# Generated by innovus_enablement/scripts/gen_fakeram.py: abstract 512x64 SRAM.
# Geometry is an assumption (see script header), not PDK data.
VERSION 5.8 ;
BUSBITCHARS "[]" ;
DIVIDERCHAR "/" ;

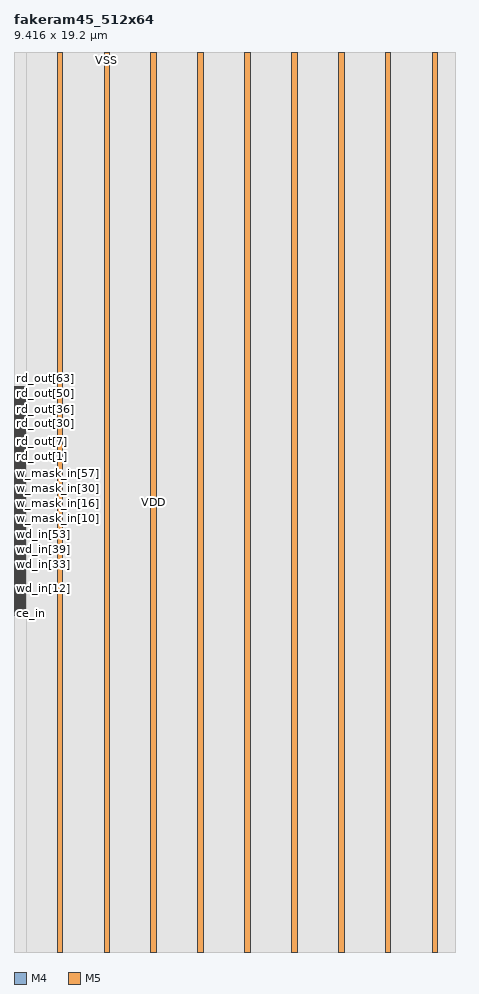
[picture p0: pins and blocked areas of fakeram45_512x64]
MACRO fakeram45_512x64
  CLASS BLOCK ;
  FOREIGN fakeram45_512x64 0 0 ;
  ORIGIN 0 0 ;
  SIZE 9.4160 BY 19.2000 ;
  SYMMETRY X Y R90 ;
  PIN clk
    DIRECTION INPUT ;
    USE CLOCK ;
    PORT
      LAYER M4 ;
        RECT 0 7.1820 0.2400 7.1940 ;
    END
  END clk
  PIN ce_in
    DIRECTION INPUT ;
    USE SIGNAL ;
    PORT
      LAYER M4 ;
        RECT 0 7.2060 0.2400 7.2180 ;
    END
  END ce_in
  PIN we_in
    DIRECTION INPUT ;
    USE SIGNAL ;
    PORT
      LAYER M4 ;
        RECT 0 7.2300 0.2400 7.2420 ;
    END
  END we_in
  PIN addr_in[0]
    DIRECTION INPUT ;
    USE SIGNAL ;
    PORT
      LAYER M4 ;
        RECT 0 7.2540 0.2400 7.2660 ;
    END
  END addr_in[0]
  PIN addr_in[1]
    DIRECTION INPUT ;
    USE SIGNAL ;
    PORT
      LAYER M4 ;
        RECT 0 7.2780 0.2400 7.2900 ;
    END
  END addr_in[1]
  PIN addr_in[2]
    DIRECTION INPUT ;
    USE SIGNAL ;
    PORT
      LAYER M4 ;
        RECT 0 7.3020 0.2400 7.3140 ;
    END
  END addr_in[2]
  PIN addr_in[3]
    DIRECTION INPUT ;
    USE SIGNAL ;
    PORT
      LAYER M4 ;
        RECT 0 7.3260 0.2400 7.3380 ;
    END
  END addr_in[3]
  PIN addr_in[4]
    DIRECTION INPUT ;
    USE SIGNAL ;
    PORT
      LAYER M4 ;
        RECT 0 7.3500 0.2400 7.3620 ;
    END
  END addr_in[4]
  PIN addr_in[5]
    DIRECTION INPUT ;
    USE SIGNAL ;
    PORT
      LAYER M4 ;
        RECT 0 7.3740 0.2400 7.3860 ;
    END
  END addr_in[5]
  PIN addr_in[6]
    DIRECTION INPUT ;
    USE SIGNAL ;
    PORT
      LAYER M4 ;
        RECT 0 7.3980 0.2400 7.4100 ;
    END
  END addr_in[6]
  PIN addr_in[7]
    DIRECTION INPUT ;
    USE SIGNAL ;
    PORT
      LAYER M4 ;
        RECT 0 7.4220 0.2400 7.4340 ;
    END
  END addr_in[7]
  PIN addr_in[8]
    DIRECTION INPUT ;
    USE SIGNAL ;
    PORT
      LAYER M4 ;
        RECT 0 7.4460 0.2400 7.4580 ;
    END
  END addr_in[8]
  PIN wd_in[0]
    DIRECTION INPUT ;
    USE SIGNAL ;
    PORT
      LAYER M4 ;
        RECT 0 7.4700 0.2400 7.4820 ;
    END
  END wd_in[0]
  PIN wd_in[1]
    DIRECTION INPUT ;
    USE SIGNAL ;
    PORT
      LAYER M4 ;
        RECT 0 7.4940 0.2400 7.5060 ;
    END
  END wd_in[1]
  PIN wd_in[2]
    DIRECTION INPUT ;
    USE SIGNAL ;
    PORT
      LAYER M4 ;
        RECT 0 7.5180 0.2400 7.5300 ;
    END
  END wd_in[2]
  PIN wd_in[3]
    DIRECTION INPUT ;
    USE SIGNAL ;
    PORT
      LAYER M4 ;
        RECT 0 7.5420 0.2400 7.5540 ;
    END
  END wd_in[3]
  PIN wd_in[4]
    DIRECTION INPUT ;
    USE SIGNAL ;
    PORT
      LAYER M4 ;
        RECT 0 7.5660 0.2400 7.5780 ;
    END
  END wd_in[4]
  PIN wd_in[5]
    DIRECTION INPUT ;
    USE SIGNAL ;
    PORT
      LAYER M4 ;
        RECT 0 7.5900 0.2400 7.6020 ;
    END
  END wd_in[5]
  PIN wd_in[6]
    DIRECTION INPUT ;
    USE SIGNAL ;
    PORT
      LAYER M4 ;
        RECT 0 7.6140 0.2400 7.6260 ;
    END
  END wd_in[6]
  PIN wd_in[7]
    DIRECTION INPUT ;
    USE SIGNAL ;
    PORT
      LAYER M4 ;
        RECT 0 7.6380 0.2400 7.6500 ;
    END
  END wd_in[7]
  PIN wd_in[8]
    DIRECTION INPUT ;
    USE SIGNAL ;
    PORT
      LAYER M4 ;
        RECT 0 7.6620 0.2400 7.6740 ;
    END
  END wd_in[8]
  PIN wd_in[9]
    DIRECTION INPUT ;
    USE SIGNAL ;
    PORT
      LAYER M4 ;
        RECT 0 7.6860 0.2400 7.6980 ;
    END
  END wd_in[9]
  PIN wd_in[10]
    DIRECTION INPUT ;
    USE SIGNAL ;
    PORT
      LAYER M4 ;
        RECT 0 7.7100 0.2400 7.7220 ;
    END
  END wd_in[10]
  PIN wd_in[11]
    DIRECTION INPUT ;
    USE SIGNAL ;
    PORT
      LAYER M4 ;
        RECT 0 7.7340 0.2400 7.7460 ;
    END
  END wd_in[11]
  PIN wd_in[12]
    DIRECTION INPUT ;
    USE SIGNAL ;
    PORT
      LAYER M4 ;
        RECT 0 7.7580 0.2400 7.7700 ;
    END
  END wd_in[12]
  PIN wd_in[13]
    DIRECTION INPUT ;
    USE SIGNAL ;
    PORT
      LAYER M4 ;
        RECT 0 7.7820 0.2400 7.7940 ;
    END
  END wd_in[13]
  PIN wd_in[14]
    DIRECTION INPUT ;
    USE SIGNAL ;
    PORT
      LAYER M4 ;
        RECT 0 7.8060 0.2400 7.8180 ;
    END
  END wd_in[14]
  PIN wd_in[15]
    DIRECTION INPUT ;
    USE SIGNAL ;
    PORT
      LAYER M4 ;
        RECT 0 7.8300 0.2400 7.8420 ;
    END
  END wd_in[15]
  PIN wd_in[16]
    DIRECTION INPUT ;
    USE SIGNAL ;
    PORT
      LAYER M4 ;
        RECT 0 7.8540 0.2400 7.8660 ;
    END
  END wd_in[16]
  PIN wd_in[17]
    DIRECTION INPUT ;
    USE SIGNAL ;
    PORT
      LAYER M4 ;
        RECT 0 7.8780 0.2400 7.8900 ;
    END
  END wd_in[17]
  PIN wd_in[18]
    DIRECTION INPUT ;
    USE SIGNAL ;
    PORT
      LAYER M4 ;
        RECT 0 7.9020 0.2400 7.9140 ;
    END
  END wd_in[18]
  PIN wd_in[19]
    DIRECTION INPUT ;
    USE SIGNAL ;
    PORT
      LAYER M4 ;
        RECT 0 7.9260 0.2400 7.9380 ;
    END
  END wd_in[19]
  PIN wd_in[20]
    DIRECTION INPUT ;
    USE SIGNAL ;
    PORT
      LAYER M4 ;
        RECT 0 7.9500 0.2400 7.9620 ;
    END
  END wd_in[20]
  PIN wd_in[21]
    DIRECTION INPUT ;
    USE SIGNAL ;
    PORT
      LAYER M4 ;
        RECT 0 7.9740 0.2400 7.9860 ;
    END
  END wd_in[21]
  PIN wd_in[22]
    DIRECTION INPUT ;
    USE SIGNAL ;
    PORT
      LAYER M4 ;
        RECT 0 7.9980 0.2400 8.0100 ;
    END
  END wd_in[22]
  PIN wd_in[23]
    DIRECTION INPUT ;
    USE SIGNAL ;
    PORT
      LAYER M4 ;
        RECT 0 8.0220 0.2400 8.0340 ;
    END
  END wd_in[23]
  PIN wd_in[24]
    DIRECTION INPUT ;
    USE SIGNAL ;
    PORT
      LAYER M4 ;
        RECT 0 8.0460 0.2400 8.0580 ;
    END
  END wd_in[24]
  PIN wd_in[25]
    DIRECTION INPUT ;
    USE SIGNAL ;
    PORT
      LAYER M4 ;
        RECT 0 8.0700 0.2400 8.0820 ;
    END
  END wd_in[25]
  PIN wd_in[26]
    DIRECTION INPUT ;
    USE SIGNAL ;
    PORT
      LAYER M4 ;
        RECT 0 8.0940 0.2400 8.1060 ;
    END
  END wd_in[26]
  PIN wd_in[27]
    DIRECTION INPUT ;
    USE SIGNAL ;
    PORT
      LAYER M4 ;
        RECT 0 8.1180 0.2400 8.1300 ;
    END
  END wd_in[27]
  PIN wd_in[28]
    DIRECTION INPUT ;
    USE SIGNAL ;
    PORT
      LAYER M4 ;
        RECT 0 8.1420 0.2400 8.1540 ;
    END
  END wd_in[28]
  PIN wd_in[29]
    DIRECTION INPUT ;
    USE SIGNAL ;
    PORT
      LAYER M4 ;
        RECT 0 8.1660 0.2400 8.1780 ;
    END
  END wd_in[29]
  PIN wd_in[30]
    DIRECTION INPUT ;
    USE SIGNAL ;
    PORT
      LAYER M4 ;
        RECT 0 8.1900 0.2400 8.2020 ;
    END
  END wd_in[30]
  PIN wd_in[31]
    DIRECTION INPUT ;
    USE SIGNAL ;
    PORT
      LAYER M4 ;
        RECT 0 8.2140 0.2400 8.2260 ;
    END
  END wd_in[31]
  PIN wd_in[32]
    DIRECTION INPUT ;
    USE SIGNAL ;
    PORT
      LAYER M4 ;
        RECT 0 8.2380 0.2400 8.2500 ;
    END
  END wd_in[32]
  PIN wd_in[33]
    DIRECTION INPUT ;
    USE SIGNAL ;
    PORT
      LAYER M4 ;
        RECT 0 8.2620 0.2400 8.2740 ;
    END
  END wd_in[33]
  PIN wd_in[34]
    DIRECTION INPUT ;
    USE SIGNAL ;
    PORT
      LAYER M4 ;
        RECT 0 8.2860 0.2400 8.2980 ;
    END
  END wd_in[34]
  PIN wd_in[35]
    DIRECTION INPUT ;
    USE SIGNAL ;
    PORT
      LAYER M4 ;
        RECT 0 8.3100 0.2400 8.3220 ;
    END
  END wd_in[35]
  PIN wd_in[36]
    DIRECTION INPUT ;
    USE SIGNAL ;
    PORT
      LAYER M4 ;
        RECT 0 8.3340 0.2400 8.3460 ;
    END
  END wd_in[36]
  PIN wd_in[37]
    DIRECTION INPUT ;
    USE SIGNAL ;
    PORT
      LAYER M4 ;
        RECT 0 8.3580 0.2400 8.3700 ;
    END
  END wd_in[37]
  PIN wd_in[38]
    DIRECTION INPUT ;
    USE SIGNAL ;
    PORT
      LAYER M4 ;
        RECT 0 8.3820 0.2400 8.3940 ;
    END
  END wd_in[38]
  PIN wd_in[39]
    DIRECTION INPUT ;
    USE SIGNAL ;
    PORT
      LAYER M4 ;
        RECT 0 8.4060 0.2400 8.4180 ;
    END
  END wd_in[39]
  PIN wd_in[40]
    DIRECTION INPUT ;
    USE SIGNAL ;
    PORT
      LAYER M4 ;
        RECT 0 8.4300 0.2400 8.4420 ;
    END
  END wd_in[40]
  PIN wd_in[41]
    DIRECTION INPUT ;
    USE SIGNAL ;
    PORT
      LAYER M4 ;
        RECT 0 8.4540 0.2400 8.4660 ;
    END
  END wd_in[41]
  PIN wd_in[42]
    DIRECTION INPUT ;
    USE SIGNAL ;
    PORT
      LAYER M4 ;
        RECT 0 8.4780 0.2400 8.4900 ;
    END
  END wd_in[42]
  PIN wd_in[43]
    DIRECTION INPUT ;
    USE SIGNAL ;
    PORT
      LAYER M4 ;
        RECT 0 8.5020 0.2400 8.5140 ;
    END
  END wd_in[43]
  PIN wd_in[44]
    DIRECTION INPUT ;
    USE SIGNAL ;
    PORT
      LAYER M4 ;
        RECT 0 8.5260 0.2400 8.5380 ;
    END
  END wd_in[44]
  PIN wd_in[45]
    DIRECTION INPUT ;
    USE SIGNAL ;
    PORT
      LAYER M4 ;
        RECT 0 8.5500 0.2400 8.5620 ;
    END
  END wd_in[45]
  PIN wd_in[46]
    DIRECTION INPUT ;
    USE SIGNAL ;
    PORT
      LAYER M4 ;
        RECT 0 8.5740 0.2400 8.5860 ;
    END
  END wd_in[46]
  PIN wd_in[47]
    DIRECTION INPUT ;
    USE SIGNAL ;
    PORT
      LAYER M4 ;
        RECT 0 8.5980 0.2400 8.6100 ;
    END
  END wd_in[47]
  PIN wd_in[48]
    DIRECTION INPUT ;
    USE SIGNAL ;
    PORT
      LAYER M4 ;
        RECT 0 8.6220 0.2400 8.6340 ;
    END
  END wd_in[48]
  PIN wd_in[49]
    DIRECTION INPUT ;
    USE SIGNAL ;
    PORT
      LAYER M4 ;
        RECT 0 8.6460 0.2400 8.6580 ;
    END
  END wd_in[49]
  PIN wd_in[50]
    DIRECTION INPUT ;
    USE SIGNAL ;
    PORT
      LAYER M4 ;
        RECT 0 8.6700 0.2400 8.6820 ;
    END
  END wd_in[50]
  PIN wd_in[51]
    DIRECTION INPUT ;
    USE SIGNAL ;
    PORT
      LAYER M4 ;
        RECT 0 8.6940 0.2400 8.7060 ;
    END
  END wd_in[51]
  PIN wd_in[52]
    DIRECTION INPUT ;
    USE SIGNAL ;
    PORT
      LAYER M4 ;
        RECT 0 8.7180 0.2400 8.7300 ;
    END
  END wd_in[52]
  PIN wd_in[53]
    DIRECTION INPUT ;
    USE SIGNAL ;
    PORT
      LAYER M4 ;
        RECT 0 8.7420 0.2400 8.7540 ;
    END
  END wd_in[53]
  PIN wd_in[54]
    DIRECTION INPUT ;
    USE SIGNAL ;
    PORT
      LAYER M4 ;
        RECT 0 8.7660 0.2400 8.7780 ;
    END
  END wd_in[54]
  PIN wd_in[55]
    DIRECTION INPUT ;
    USE SIGNAL ;
    PORT
      LAYER M4 ;
        RECT 0 8.7900 0.2400 8.8020 ;
    END
  END wd_in[55]
  PIN wd_in[56]
    DIRECTION INPUT ;
    USE SIGNAL ;
    PORT
      LAYER M4 ;
        RECT 0 8.8140 0.2400 8.8260 ;
    END
  END wd_in[56]
  PIN wd_in[57]
    DIRECTION INPUT ;
    USE SIGNAL ;
    PORT
      LAYER M4 ;
        RECT 0 8.8380 0.2400 8.8500 ;
    END
  END wd_in[57]
  PIN wd_in[58]
    DIRECTION INPUT ;
    USE SIGNAL ;
    PORT
      LAYER M4 ;
        RECT 0 8.8620 0.2400 8.8740 ;
    END
  END wd_in[58]
  PIN wd_in[59]
    DIRECTION INPUT ;
    USE SIGNAL ;
    PORT
      LAYER M4 ;
        RECT 0 8.8860 0.2400 8.8980 ;
    END
  END wd_in[59]
  PIN wd_in[60]
    DIRECTION INPUT ;
    USE SIGNAL ;
    PORT
      LAYER M4 ;
        RECT 0 8.9100 0.2400 8.9220 ;
    END
  END wd_in[60]
  PIN wd_in[61]
    DIRECTION INPUT ;
    USE SIGNAL ;
    PORT
      LAYER M4 ;
        RECT 0 8.9340 0.2400 8.9460 ;
    END
  END wd_in[61]
  PIN wd_in[62]
    DIRECTION INPUT ;
    USE SIGNAL ;
    PORT
      LAYER M4 ;
        RECT 0 8.9580 0.2400 8.9700 ;
    END
  END wd_in[62]
  PIN wd_in[63]
    DIRECTION INPUT ;
    USE SIGNAL ;
    PORT
      LAYER M4 ;
        RECT 0 8.9820 0.2400 8.9940 ;
    END
  END wd_in[63]
  PIN w_mask_in[0]
    DIRECTION INPUT ;
    USE SIGNAL ;
    PORT
      LAYER M4 ;
        RECT 0 9.0060 0.2400 9.0180 ;
    END
  END w_mask_in[0]
  PIN w_mask_in[1]
    DIRECTION INPUT ;
    USE SIGNAL ;
    PORT
      LAYER M4 ;
        RECT 0 9.0300 0.2400 9.0420 ;
    END
  END w_mask_in[1]
  PIN w_mask_in[2]
    DIRECTION INPUT ;
    USE SIGNAL ;
    PORT
      LAYER M4 ;
        RECT 0 9.0540 0.2400 9.0660 ;
    END
  END w_mask_in[2]
  PIN w_mask_in[3]
    DIRECTION INPUT ;
    USE SIGNAL ;
    PORT
      LAYER M4 ;
        RECT 0 9.0780 0.2400 9.0900 ;
    END
  END w_mask_in[3]
  PIN w_mask_in[4]
    DIRECTION INPUT ;
    USE SIGNAL ;
    PORT
      LAYER M4 ;
        RECT 0 9.1020 0.2400 9.1140 ;
    END
  END w_mask_in[4]
  PIN w_mask_in[5]
    DIRECTION INPUT ;
    USE SIGNAL ;
    PORT
      LAYER M4 ;
        RECT 0 9.1260 0.2400 9.1380 ;
    END
  END w_mask_in[5]
  PIN w_mask_in[6]
    DIRECTION INPUT ;
    USE SIGNAL ;
    PORT
      LAYER M4 ;
        RECT 0 9.1500 0.2400 9.1620 ;
    END
  END w_mask_in[6]
  PIN w_mask_in[7]
    DIRECTION INPUT ;
    USE SIGNAL ;
    PORT
      LAYER M4 ;
        RECT 0 9.1740 0.2400 9.1860 ;
    END
  END w_mask_in[7]
  PIN w_mask_in[8]
    DIRECTION INPUT ;
    USE SIGNAL ;
    PORT
      LAYER M4 ;
        RECT 0 9.1980 0.2400 9.2100 ;
    END
  END w_mask_in[8]
  PIN w_mask_in[9]
    DIRECTION INPUT ;
    USE SIGNAL ;
    PORT
      LAYER M4 ;
        RECT 0 9.2220 0.2400 9.2340 ;
    END
  END w_mask_in[9]
  PIN w_mask_in[10]
    DIRECTION INPUT ;
    USE SIGNAL ;
    PORT
      LAYER M4 ;
        RECT 0 9.2460 0.2400 9.2580 ;
    END
  END w_mask_in[10]
  PIN w_mask_in[11]
    DIRECTION INPUT ;
    USE SIGNAL ;
    PORT
      LAYER M4 ;
        RECT 0 9.2700 0.2400 9.2820 ;
    END
  END w_mask_in[11]
  PIN w_mask_in[12]
    DIRECTION INPUT ;
    USE SIGNAL ;
    PORT
      LAYER M4 ;
        RECT 0 9.2940 0.2400 9.3060 ;
    END
  END w_mask_in[12]
  PIN w_mask_in[13]
    DIRECTION INPUT ;
    USE SIGNAL ;
    PORT
      LAYER M4 ;
        RECT 0 9.3180 0.2400 9.3300 ;
    END
  END w_mask_in[13]
  PIN w_mask_in[14]
    DIRECTION INPUT ;
    USE SIGNAL ;
    PORT
      LAYER M4 ;
        RECT 0 9.3420 0.2400 9.3540 ;
    END
  END w_mask_in[14]
  PIN w_mask_in[15]
    DIRECTION INPUT ;
    USE SIGNAL ;
    PORT
      LAYER M4 ;
        RECT 0 9.3660 0.2400 9.3780 ;
    END
  END w_mask_in[15]
  PIN w_mask_in[16]
    DIRECTION INPUT ;
    USE SIGNAL ;
    PORT
      LAYER M4 ;
        RECT 0 9.3900 0.2400 9.4020 ;
    END
  END w_mask_in[16]
  PIN w_mask_in[17]
    DIRECTION INPUT ;
    USE SIGNAL ;
    PORT
      LAYER M4 ;
        RECT 0 9.4140 0.2400 9.4260 ;
    END
  END w_mask_in[17]
  PIN w_mask_in[18]
    DIRECTION INPUT ;
    USE SIGNAL ;
    PORT
      LAYER M4 ;
        RECT 0 9.4380 0.2400 9.4500 ;
    END
  END w_mask_in[18]
  PIN w_mask_in[19]
    DIRECTION INPUT ;
    USE SIGNAL ;
    PORT
      LAYER M4 ;
        RECT 0 9.4620 0.2400 9.4740 ;
    END
  END w_mask_in[19]
  PIN w_mask_in[20]
    DIRECTION INPUT ;
    USE SIGNAL ;
    PORT
      LAYER M4 ;
        RECT 0 9.4860 0.2400 9.4980 ;
    END
  END w_mask_in[20]
  PIN w_mask_in[21]
    DIRECTION INPUT ;
    USE SIGNAL ;
    PORT
      LAYER M4 ;
        RECT 0 9.5100 0.2400 9.5220 ;
    END
  END w_mask_in[21]
  PIN w_mask_in[22]
    DIRECTION INPUT ;
    USE SIGNAL ;
    PORT
      LAYER M4 ;
        RECT 0 9.5340 0.2400 9.5460 ;
    END
  END w_mask_in[22]
  PIN w_mask_in[23]
    DIRECTION INPUT ;
    USE SIGNAL ;
    PORT
      LAYER M4 ;
        RECT 0 9.5580 0.2400 9.5700 ;
    END
  END w_mask_in[23]
  PIN w_mask_in[24]
    DIRECTION INPUT ;
    USE SIGNAL ;
    PORT
      LAYER M4 ;
        RECT 0 9.5820 0.2400 9.5940 ;
    END
  END w_mask_in[24]
  PIN w_mask_in[25]
    DIRECTION INPUT ;
    USE SIGNAL ;
    PORT
      LAYER M4 ;
        RECT 0 9.6060 0.2400 9.6180 ;
    END
  END w_mask_in[25]
  PIN w_mask_in[26]
    DIRECTION INPUT ;
    USE SIGNAL ;
    PORT
      LAYER M4 ;
        RECT 0 9.6300 0.2400 9.6420 ;
    END
  END w_mask_in[26]
  PIN w_mask_in[27]
    DIRECTION INPUT ;
    USE SIGNAL ;
    PORT
      LAYER M4 ;
        RECT 0 9.6540 0.2400 9.6660 ;
    END
  END w_mask_in[27]
  PIN w_mask_in[28]
    DIRECTION INPUT ;
    USE SIGNAL ;
    PORT
      LAYER M4 ;
        RECT 0 9.6780 0.2400 9.6900 ;
    END
  END w_mask_in[28]
  PIN w_mask_in[29]
    DIRECTION INPUT ;
    USE SIGNAL ;
    PORT
      LAYER M4 ;
        RECT 0 9.7020 0.2400 9.7140 ;
    END
  END w_mask_in[29]
  PIN w_mask_in[30]
    DIRECTION INPUT ;
    USE SIGNAL ;
    PORT
      LAYER M4 ;
        RECT 0 9.7260 0.2400 9.7380 ;
    END
  END w_mask_in[30]
  PIN w_mask_in[31]
    DIRECTION INPUT ;
    USE SIGNAL ;
    PORT
      LAYER M4 ;
        RECT 0 9.7500 0.2400 9.7620 ;
    END
  END w_mask_in[31]
  PIN w_mask_in[32]
    DIRECTION INPUT ;
    USE SIGNAL ;
    PORT
      LAYER M4 ;
        RECT 0 9.7740 0.2400 9.7860 ;
    END
  END w_mask_in[32]
  PIN w_mask_in[33]
    DIRECTION INPUT ;
    USE SIGNAL ;
    PORT
      LAYER M4 ;
        RECT 0 9.7980 0.2400 9.8100 ;
    END
  END w_mask_in[33]
  PIN w_mask_in[34]
    DIRECTION INPUT ;
    USE SIGNAL ;
    PORT
      LAYER M4 ;
        RECT 0 9.8220 0.2400 9.8340 ;
    END
  END w_mask_in[34]
  PIN w_mask_in[35]
    DIRECTION INPUT ;
    USE SIGNAL ;
    PORT
      LAYER M4 ;
        RECT 0 9.8460 0.2400 9.8580 ;
    END
  END w_mask_in[35]
  PIN w_mask_in[36]
    DIRECTION INPUT ;
    USE SIGNAL ;
    PORT
      LAYER M4 ;
        RECT 0 9.8700 0.2400 9.8820 ;
    END
  END w_mask_in[36]
  PIN w_mask_in[37]
    DIRECTION INPUT ;
    USE SIGNAL ;
    PORT
      LAYER M4 ;
        RECT 0 9.8940 0.2400 9.9060 ;
    END
  END w_mask_in[37]
  PIN w_mask_in[38]
    DIRECTION INPUT ;
    USE SIGNAL ;
    PORT
      LAYER M4 ;
        RECT 0 9.9180 0.2400 9.9300 ;
    END
  END w_mask_in[38]
  PIN w_mask_in[39]
    DIRECTION INPUT ;
    USE SIGNAL ;
    PORT
      LAYER M4 ;
        RECT 0 9.9420 0.2400 9.9540 ;
    END
  END w_mask_in[39]
  PIN w_mask_in[40]
    DIRECTION INPUT ;
    USE SIGNAL ;
    PORT
      LAYER M4 ;
        RECT 0 9.9660 0.2400 9.9780 ;
    END
  END w_mask_in[40]
  PIN w_mask_in[41]
    DIRECTION INPUT ;
    USE SIGNAL ;
    PORT
      LAYER M4 ;
        RECT 0 9.9900 0.2400 10.0020 ;
    END
  END w_mask_in[41]
  PIN w_mask_in[42]
    DIRECTION INPUT ;
    USE SIGNAL ;
    PORT
      LAYER M4 ;
        RECT 0 10.0140 0.2400 10.0260 ;
    END
  END w_mask_in[42]
  PIN w_mask_in[43]
    DIRECTION INPUT ;
    USE SIGNAL ;
    PORT
      LAYER M4 ;
        RECT 0 10.0380 0.2400 10.0500 ;
    END
  END w_mask_in[43]
  PIN w_mask_in[44]
    DIRECTION INPUT ;
    USE SIGNAL ;
    PORT
      LAYER M4 ;
        RECT 0 10.0620 0.2400 10.0740 ;
    END
  END w_mask_in[44]
  PIN w_mask_in[45]
    DIRECTION INPUT ;
    USE SIGNAL ;
    PORT
      LAYER M4 ;
        RECT 0 10.0860 0.2400 10.0980 ;
    END
  END w_mask_in[45]
  PIN w_mask_in[46]
    DIRECTION INPUT ;
    USE SIGNAL ;
    PORT
      LAYER M4 ;
        RECT 0 10.1100 0.2400 10.1220 ;
    END
  END w_mask_in[46]
  PIN w_mask_in[47]
    DIRECTION INPUT ;
    USE SIGNAL ;
    PORT
      LAYER M4 ;
        RECT 0 10.1340 0.2400 10.1460 ;
    END
  END w_mask_in[47]
  PIN w_mask_in[48]
    DIRECTION INPUT ;
    USE SIGNAL ;
    PORT
      LAYER M4 ;
        RECT 0 10.1580 0.2400 10.1700 ;
    END
  END w_mask_in[48]
  PIN w_mask_in[49]
    DIRECTION INPUT ;
    USE SIGNAL ;
    PORT
      LAYER M4 ;
        RECT 0 10.1820 0.2400 10.1940 ;
    END
  END w_mask_in[49]
  PIN w_mask_in[50]
    DIRECTION INPUT ;
    USE SIGNAL ;
    PORT
      LAYER M4 ;
        RECT 0 10.2060 0.2400 10.2180 ;
    END
  END w_mask_in[50]
  PIN w_mask_in[51]
    DIRECTION INPUT ;
    USE SIGNAL ;
    PORT
      LAYER M4 ;
        RECT 0 10.2300 0.2400 10.2420 ;
    END
  END w_mask_in[51]
  PIN w_mask_in[52]
    DIRECTION INPUT ;
    USE SIGNAL ;
    PORT
      LAYER M4 ;
        RECT 0 10.2540 0.2400 10.2660 ;
    END
  END w_mask_in[52]
  PIN w_mask_in[53]
    DIRECTION INPUT ;
    USE SIGNAL ;
    PORT
      LAYER M4 ;
        RECT 0 10.2780 0.2400 10.2900 ;
    END
  END w_mask_in[53]
  PIN w_mask_in[54]
    DIRECTION INPUT ;
    USE SIGNAL ;
    PORT
      LAYER M4 ;
        RECT 0 10.3020 0.2400 10.3140 ;
    END
  END w_mask_in[54]
  PIN w_mask_in[55]
    DIRECTION INPUT ;
    USE SIGNAL ;
    PORT
      LAYER M4 ;
        RECT 0 10.3260 0.2400 10.3380 ;
    END
  END w_mask_in[55]
  PIN w_mask_in[56]
    DIRECTION INPUT ;
    USE SIGNAL ;
    PORT
      LAYER M4 ;
        RECT 0 10.3500 0.2400 10.3620 ;
    END
  END w_mask_in[56]
  PIN w_mask_in[57]
    DIRECTION INPUT ;
    USE SIGNAL ;
    PORT
      LAYER M4 ;
        RECT 0 10.3740 0.2400 10.3860 ;
    END
  END w_mask_in[57]
  PIN w_mask_in[58]
    DIRECTION INPUT ;
    USE SIGNAL ;
    PORT
      LAYER M4 ;
        RECT 0 10.3980 0.2400 10.4100 ;
    END
  END w_mask_in[58]
  PIN w_mask_in[59]
    DIRECTION INPUT ;
    USE SIGNAL ;
    PORT
      LAYER M4 ;
        RECT 0 10.4220 0.2400 10.4340 ;
    END
  END w_mask_in[59]
  PIN w_mask_in[60]
    DIRECTION INPUT ;
    USE SIGNAL ;
    PORT
      LAYER M4 ;
        RECT 0 10.4460 0.2400 10.4580 ;
    END
  END w_mask_in[60]
  PIN w_mask_in[61]
    DIRECTION INPUT ;
    USE SIGNAL ;
    PORT
      LAYER M4 ;
        RECT 0 10.4700 0.2400 10.4820 ;
    END
  END w_mask_in[61]
  PIN w_mask_in[62]
    DIRECTION INPUT ;
    USE SIGNAL ;
    PORT
      LAYER M4 ;
        RECT 0 10.4940 0.2400 10.5060 ;
    END
  END w_mask_in[62]
  PIN w_mask_in[63]
    DIRECTION INPUT ;
    USE SIGNAL ;
    PORT
      LAYER M4 ;
        RECT 0 10.5180 0.2400 10.5300 ;
    END
  END w_mask_in[63]
  PIN rd_out[0]
    DIRECTION OUTPUT ;
    USE SIGNAL ;
    PORT
      LAYER M4 ;
        RECT 0 10.5420 0.2400 10.5540 ;
    END
  END rd_out[0]
  PIN rd_out[1]
    DIRECTION OUTPUT ;
    USE SIGNAL ;
    PORT
      LAYER M4 ;
        RECT 0 10.5660 0.2400 10.5780 ;
    END
  END rd_out[1]
  PIN rd_out[2]
    DIRECTION OUTPUT ;
    USE SIGNAL ;
    PORT
      LAYER M4 ;
        RECT 0 10.5900 0.2400 10.6020 ;
    END
  END rd_out[2]
  PIN rd_out[3]
    DIRECTION OUTPUT ;
    USE SIGNAL ;
    PORT
      LAYER M4 ;
        RECT 0 10.6140 0.2400 10.6260 ;
    END
  END rd_out[3]
  PIN rd_out[4]
    DIRECTION OUTPUT ;
    USE SIGNAL ;
    PORT
      LAYER M4 ;
        RECT 0 10.6380 0.2400 10.6500 ;
    END
  END rd_out[4]
  PIN rd_out[5]
    DIRECTION OUTPUT ;
    USE SIGNAL ;
    PORT
      LAYER M4 ;
        RECT 0 10.6620 0.2400 10.6740 ;
    END
  END rd_out[5]
  PIN rd_out[6]
    DIRECTION OUTPUT ;
    USE SIGNAL ;
    PORT
      LAYER M4 ;
        RECT 0 10.6860 0.2400 10.6980 ;
    END
  END rd_out[6]
  PIN rd_out[7]
    DIRECTION OUTPUT ;
    USE SIGNAL ;
    PORT
      LAYER M4 ;
        RECT 0 10.7100 0.2400 10.7220 ;
    END
  END rd_out[7]
  PIN rd_out[8]
    DIRECTION OUTPUT ;
    USE SIGNAL ;
    PORT
      LAYER M4 ;
        RECT 0 10.7340 0.2400 10.7460 ;
    END
  END rd_out[8]
  PIN rd_out[9]
    DIRECTION OUTPUT ;
    USE SIGNAL ;
    PORT
      LAYER M4 ;
        RECT 0 10.7580 0.2400 10.7700 ;
    END
  END rd_out[9]
  PIN rd_out[10]
    DIRECTION OUTPUT ;
    USE SIGNAL ;
    PORT
      LAYER M4 ;
        RECT 0 10.7820 0.2400 10.7940 ;
    END
  END rd_out[10]
  PIN rd_out[11]
    DIRECTION OUTPUT ;
    USE SIGNAL ;
    PORT
      LAYER M4 ;
        RECT 0 10.8060 0.2400 10.8180 ;
    END
  END rd_out[11]
  PIN rd_out[12]
    DIRECTION OUTPUT ;
    USE SIGNAL ;
    PORT
      LAYER M4 ;
        RECT 0 10.8300 0.2400 10.8420 ;
    END
  END rd_out[12]
  PIN rd_out[13]
    DIRECTION OUTPUT ;
    USE SIGNAL ;
    PORT
      LAYER M4 ;
        RECT 0 10.8540 0.2400 10.8660 ;
    END
  END rd_out[13]
  PIN rd_out[14]
    DIRECTION OUTPUT ;
    USE SIGNAL ;
    PORT
      LAYER M4 ;
        RECT 0 10.8780 0.2400 10.8900 ;
    END
  END rd_out[14]
  PIN rd_out[15]
    DIRECTION OUTPUT ;
    USE SIGNAL ;
    PORT
      LAYER M4 ;
        RECT 0 10.9020 0.2400 10.9140 ;
    END
  END rd_out[15]
  PIN rd_out[16]
    DIRECTION OUTPUT ;
    USE SIGNAL ;
    PORT
      LAYER M4 ;
        RECT 0 10.9260 0.2400 10.9380 ;
    END
  END rd_out[16]
  PIN rd_out[17]
    DIRECTION OUTPUT ;
    USE SIGNAL ;
    PORT
      LAYER M4 ;
        RECT 0 10.9500 0.2400 10.9620 ;
    END
  END rd_out[17]
  PIN rd_out[18]
    DIRECTION OUTPUT ;
    USE SIGNAL ;
    PORT
      LAYER M4 ;
        RECT 0 10.9740 0.2400 10.9860 ;
    END
  END rd_out[18]
  PIN rd_out[19]
    DIRECTION OUTPUT ;
    USE SIGNAL ;
    PORT
      LAYER M4 ;
        RECT 0 10.9980 0.2400 11.0100 ;
    END
  END rd_out[19]
  PIN rd_out[20]
    DIRECTION OUTPUT ;
    USE SIGNAL ;
    PORT
      LAYER M4 ;
        RECT 0 11.0220 0.2400 11.0340 ;
    END
  END rd_out[20]
  PIN rd_out[21]
    DIRECTION OUTPUT ;
    USE SIGNAL ;
    PORT
      LAYER M4 ;
        RECT 0 11.0460 0.2400 11.0580 ;
    END
  END rd_out[21]
  PIN rd_out[22]
    DIRECTION OUTPUT ;
    USE SIGNAL ;
    PORT
      LAYER M4 ;
        RECT 0 11.0700 0.2400 11.0820 ;
    END
  END rd_out[22]
  PIN rd_out[23]
    DIRECTION OUTPUT ;
    USE SIGNAL ;
    PORT
      LAYER M4 ;
        RECT 0 11.0940 0.2400 11.1060 ;
    END
  END rd_out[23]
  PIN rd_out[24]
    DIRECTION OUTPUT ;
    USE SIGNAL ;
    PORT
      LAYER M4 ;
        RECT 0 11.1180 0.2400 11.1300 ;
    END
  END rd_out[24]
  PIN rd_out[25]
    DIRECTION OUTPUT ;
    USE SIGNAL ;
    PORT
      LAYER M4 ;
        RECT 0 11.1420 0.2400 11.1540 ;
    END
  END rd_out[25]
  PIN rd_out[26]
    DIRECTION OUTPUT ;
    USE SIGNAL ;
    PORT
      LAYER M4 ;
        RECT 0 11.1660 0.2400 11.1780 ;
    END
  END rd_out[26]
  PIN rd_out[27]
    DIRECTION OUTPUT ;
    USE SIGNAL ;
    PORT
      LAYER M4 ;
        RECT 0 11.1900 0.2400 11.2020 ;
    END
  END rd_out[27]
  PIN rd_out[28]
    DIRECTION OUTPUT ;
    USE SIGNAL ;
    PORT
      LAYER M4 ;
        RECT 0 11.2140 0.2400 11.2260 ;
    END
  END rd_out[28]
  PIN rd_out[29]
    DIRECTION OUTPUT ;
    USE SIGNAL ;
    PORT
      LAYER M4 ;
        RECT 0 11.2380 0.2400 11.2500 ;
    END
  END rd_out[29]
  PIN rd_out[30]
    DIRECTION OUTPUT ;
    USE SIGNAL ;
    PORT
      LAYER M4 ;
        RECT 0 11.2620 0.2400 11.2740 ;
    END
  END rd_out[30]
  PIN rd_out[31]
    DIRECTION OUTPUT ;
    USE SIGNAL ;
    PORT
      LAYER M4 ;
        RECT 0 11.2860 0.2400 11.2980 ;
    END
  END rd_out[31]
  PIN rd_out[32]
    DIRECTION OUTPUT ;
    USE SIGNAL ;
    PORT
      LAYER M4 ;
        RECT 0 11.3100 0.2400 11.3220 ;
    END
  END rd_out[32]
  PIN rd_out[33]
    DIRECTION OUTPUT ;
    USE SIGNAL ;
    PORT
      LAYER M4 ;
        RECT 0 11.3340 0.2400 11.3460 ;
    END
  END rd_out[33]
  PIN rd_out[34]
    DIRECTION OUTPUT ;
    USE SIGNAL ;
    PORT
      LAYER M4 ;
        RECT 0 11.3580 0.2400 11.3700 ;
    END
  END rd_out[34]
  PIN rd_out[35]
    DIRECTION OUTPUT ;
    USE SIGNAL ;
    PORT
      LAYER M4 ;
        RECT 0 11.3820 0.2400 11.3940 ;
    END
  END rd_out[35]
  PIN rd_out[36]
    DIRECTION OUTPUT ;
    USE SIGNAL ;
    PORT
      LAYER M4 ;
        RECT 0 11.4060 0.2400 11.4180 ;
    END
  END rd_out[36]
  PIN rd_out[37]
    DIRECTION OUTPUT ;
    USE SIGNAL ;
    PORT
      LAYER M4 ;
        RECT 0 11.4300 0.2400 11.4420 ;
    END
  END rd_out[37]
  PIN rd_out[38]
    DIRECTION OUTPUT ;
    USE SIGNAL ;
    PORT
      LAYER M4 ;
        RECT 0 11.4540 0.2400 11.4660 ;
    END
  END rd_out[38]
  PIN rd_out[39]
    DIRECTION OUTPUT ;
    USE SIGNAL ;
    PORT
      LAYER M4 ;
        RECT 0 11.4780 0.2400 11.4900 ;
    END
  END rd_out[39]
  PIN rd_out[40]
    DIRECTION OUTPUT ;
    USE SIGNAL ;
    PORT
      LAYER M4 ;
        RECT 0 11.5020 0.2400 11.5140 ;
    END
  END rd_out[40]
  PIN rd_out[41]
    DIRECTION OUTPUT ;
    USE SIGNAL ;
    PORT
      LAYER M4 ;
        RECT 0 11.5260 0.2400 11.5380 ;
    END
  END rd_out[41]
  PIN rd_out[42]
    DIRECTION OUTPUT ;
    USE SIGNAL ;
    PORT
      LAYER M4 ;
        RECT 0 11.5500 0.2400 11.5620 ;
    END
  END rd_out[42]
  PIN rd_out[43]
    DIRECTION OUTPUT ;
    USE SIGNAL ;
    PORT
      LAYER M4 ;
        RECT 0 11.5740 0.2400 11.5860 ;
    END
  END rd_out[43]
  PIN rd_out[44]
    DIRECTION OUTPUT ;
    USE SIGNAL ;
    PORT
      LAYER M4 ;
        RECT 0 11.5980 0.2400 11.6100 ;
    END
  END rd_out[44]
  PIN rd_out[45]
    DIRECTION OUTPUT ;
    USE SIGNAL ;
    PORT
      LAYER M4 ;
        RECT 0 11.6220 0.2400 11.6340 ;
    END
  END rd_out[45]
  PIN rd_out[46]
    DIRECTION OUTPUT ;
    USE SIGNAL ;
    PORT
      LAYER M4 ;
        RECT 0 11.6460 0.2400 11.6580 ;
    END
  END rd_out[46]
  PIN rd_out[47]
    DIRECTION OUTPUT ;
    USE SIGNAL ;
    PORT
      LAYER M4 ;
        RECT 0 11.6700 0.2400 11.6820 ;
    END
  END rd_out[47]
  PIN rd_out[48]
    DIRECTION OUTPUT ;
    USE SIGNAL ;
    PORT
      LAYER M4 ;
        RECT 0 11.6940 0.2400 11.7060 ;
    END
  END rd_out[48]
  PIN rd_out[49]
    DIRECTION OUTPUT ;
    USE SIGNAL ;
    PORT
      LAYER M4 ;
        RECT 0 11.7180 0.2400 11.7300 ;
    END
  END rd_out[49]
  PIN rd_out[50]
    DIRECTION OUTPUT ;
    USE SIGNAL ;
    PORT
      LAYER M4 ;
        RECT 0 11.7420 0.2400 11.7540 ;
    END
  END rd_out[50]
  PIN rd_out[51]
    DIRECTION OUTPUT ;
    USE SIGNAL ;
    PORT
      LAYER M4 ;
        RECT 0 11.7660 0.2400 11.7780 ;
    END
  END rd_out[51]
  PIN rd_out[52]
    DIRECTION OUTPUT ;
    USE SIGNAL ;
    PORT
      LAYER M4 ;
        RECT 0 11.7900 0.2400 11.8020 ;
    END
  END rd_out[52]
  PIN rd_out[53]
    DIRECTION OUTPUT ;
    USE SIGNAL ;
    PORT
      LAYER M4 ;
        RECT 0 11.8140 0.2400 11.8260 ;
    END
  END rd_out[53]
  PIN rd_out[54]
    DIRECTION OUTPUT ;
    USE SIGNAL ;
    PORT
      LAYER M4 ;
        RECT 0 11.8380 0.2400 11.8500 ;
    END
  END rd_out[54]
  PIN rd_out[55]
    DIRECTION OUTPUT ;
    USE SIGNAL ;
    PORT
      LAYER M4 ;
        RECT 0 11.8620 0.2400 11.8740 ;
    END
  END rd_out[55]
  PIN rd_out[56]
    DIRECTION OUTPUT ;
    USE SIGNAL ;
    PORT
      LAYER M4 ;
        RECT 0 11.8860 0.2400 11.8980 ;
    END
  END rd_out[56]
  PIN rd_out[57]
    DIRECTION OUTPUT ;
    USE SIGNAL ;
    PORT
      LAYER M4 ;
        RECT 0 11.9100 0.2400 11.9220 ;
    END
  END rd_out[57]
  PIN rd_out[58]
    DIRECTION OUTPUT ;
    USE SIGNAL ;
    PORT
      LAYER M4 ;
        RECT 0 11.9340 0.2400 11.9460 ;
    END
  END rd_out[58]
  PIN rd_out[59]
    DIRECTION OUTPUT ;
    USE SIGNAL ;
    PORT
      LAYER M4 ;
        RECT 0 11.9580 0.2400 11.9700 ;
    END
  END rd_out[59]
  PIN rd_out[60]
    DIRECTION OUTPUT ;
    USE SIGNAL ;
    PORT
      LAYER M4 ;
        RECT 0 11.9820 0.2400 11.9940 ;
    END
  END rd_out[60]
  PIN rd_out[61]
    DIRECTION OUTPUT ;
    USE SIGNAL ;
    PORT
      LAYER M4 ;
        RECT 0 12.0060 0.2400 12.0180 ;
    END
  END rd_out[61]
  PIN rd_out[62]
    DIRECTION OUTPUT ;
    USE SIGNAL ;
    PORT
      LAYER M4 ;
        RECT 0 12.0300 0.2400 12.0420 ;
    END
  END rd_out[62]
  PIN rd_out[63]
    DIRECTION OUTPUT ;
    USE SIGNAL ;
    PORT
      LAYER M4 ;
        RECT 0 12.0540 0.2400 12.0660 ;
    END
  END rd_out[63]
  PIN VDD
    DIRECTION INOUT ;
    USE POWER ;
    PORT
      LAYER M5 ;
        RECT 0.9200 0 1.0400 19.2000 ;
        RECT 2.9200 0 3.0400 19.2000 ;
        RECT 4.9200 0 5.0400 19.2000 ;
        RECT 6.9200 0 7.0400 19.2000 ;
        RECT 8.9200 0 9.0400 19.2000 ;
    END
  END VDD
  PIN VSS
    DIRECTION INOUT ;
    USE GROUND ;
    PORT
      LAYER M5 ;
        RECT 1.9200 0 2.0400 19.2000 ;
        RECT 3.9200 0 4.0400 19.2000 ;
        RECT 5.9200 0 6.0400 19.2000 ;
        RECT 7.9200 0 8.0400 19.2000 ;
    END
  END VSS
  OBS
    LAYER M0 ;
      RECT 0 0 9.4160 19.2000 ;
    LAYER M1 ;
      RECT 0 0 9.4160 19.2000 ;
    LAYER M2 ;
      RECT 0 0 9.4160 19.2000 ;
    LAYER M3 ;
      RECT 0 0 9.4160 19.2000 ;
    LAYER VIA0 ;
      RECT 0 0 9.4160 19.2000 ;
    LAYER VIA1 ;
      RECT 0 0 9.4160 19.2000 ;
    LAYER VIA2 ;
      RECT 0 0 9.4160 19.2000 ;
    LAYER VIA3 ;
      RECT 0 0 9.4160 19.2000 ;
    LAYER M4 ;
      RECT 0.2640 0 9.4160 19.2000 ;
  END
END fakeram45_512x64

END LIBRARY
